VERSION 5.7 ;
  NOWIREEXTENSIONATPIN ON ;
  DIVIDERCHAR "/" ;
  BUSBITCHARS "[]" ;
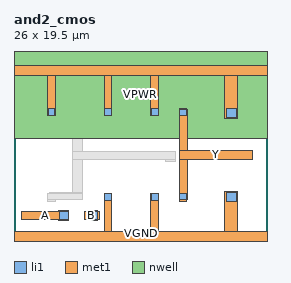
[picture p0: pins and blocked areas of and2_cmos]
MACRO and2_cmos
  CLASS BLOCK ;
  FOREIGN and2_cmos ;
  ORIGIN 0.000 0.000 ;
  SIZE 26.000 BY 19.500 ;
  PIN A
    DIRECTION INPUT ;
    USE SIGNAL ;
    ANTENNAGATEAREA 0.560000 ;
    PORT
      LAYER li1 ;
        RECT 4.650 2.150 5.550 3.050 ;
      LAYER met1 ;
        RECT 4.600 3.050 5.600 3.100 ;
        RECT 0.800 2.200 5.600 3.050 ;
        RECT 4.600 2.100 5.600 2.200 ;
    END
  END A
  PIN B
    DIRECTION INPUT ;
    USE SIGNAL ;
    ANTENNAGATEAREA 0.560000 ;
    PORT
      LAYER li1 ;
        RECT 7.650 2.150 8.550 3.050 ;
      LAYER met1 ;
        RECT 7.600 3.050 8.600 3.100 ;
        RECT 7.250 2.200 8.750 3.050 ;
        RECT 7.600 2.100 8.600 2.200 ;
    END
  END B
  PIN Y
    DIRECTION OUTPUT ;
    USE SIGNAL ;
    ANTENNADIFFAREA 6.440000 ;
    PORT
      LAYER li1 ;
        RECT 17.000 12.900 17.700 13.600 ;
        RECT 17.000 4.150 17.700 4.850 ;
      LAYER met1 ;
        RECT 16.950 13.500 17.750 13.650 ;
        RECT 16.950 9.300 17.850 13.500 ;
        RECT 16.950 8.400 24.500 9.300 ;
        RECT 16.950 4.250 17.850 8.400 ;
        RECT 16.950 4.100 17.750 4.250 ;
    END
  END Y
  PIN VPWR
    DIRECTION INOUT ;
    USE POWER ;
    PORT
      LAYER nwell ;
        RECT 0.000 10.500 26.000 19.500 ;
      LAYER li1 ;
        RECT 3.500 12.900 4.200 13.600 ;
        RECT 9.300 12.900 10.000 13.600 ;
        RECT 14.100 12.900 14.800 13.600 ;
        RECT 21.800 12.700 22.800 13.600 ;
      LAYER met1 ;
        RECT 0.000 17.000 26.000 18.000 ;
        RECT 3.450 12.850 4.250 17.000 ;
        RECT 9.250 12.850 10.050 17.000 ;
        RECT 14.050 12.850 14.850 17.000 ;
        RECT 21.650 12.600 22.950 17.000 ;
    END
  END VPWR
  PIN VGND
    DIRECTION INOUT ;
    USE GROUND ;
    PORT
      LAYER li1 ;
        RECT 9.300 4.150 10.000 4.850 ;
        RECT 14.100 4.150 14.800 4.850 ;
        RECT 21.800 4.100 22.800 5.000 ;
      LAYER met1 ;
        RECT 9.250 1.000 10.050 4.900 ;
        RECT 14.050 1.000 14.850 4.900 ;
        RECT 21.650 1.000 22.950 5.100 ;
        RECT 0.000 0.000 26.000 1.000 ;
    END
  END VGND
  OBS
      LAYER li1 ;
        RECT 6.100 12.900 6.800 13.600 ;
        RECT 15.650 8.250 16.550 9.150 ;
        RECT 3.500 4.150 4.200 4.850 ;
      LAYER met1 ;
        RECT 6.050 13.500 6.850 13.650 ;
        RECT 6.000 9.200 7.000 13.500 ;
        RECT 6.000 8.400 16.600 9.200 ;
        RECT 6.000 4.950 7.000 8.400 ;
        RECT 15.600 8.200 16.600 8.400 ;
        RECT 3.600 4.900 7.000 4.950 ;
        RECT 3.450 4.250 7.000 4.900 ;
        RECT 3.450 4.100 4.250 4.250 ;
  END
END and2_cmos
END LIBRARY

